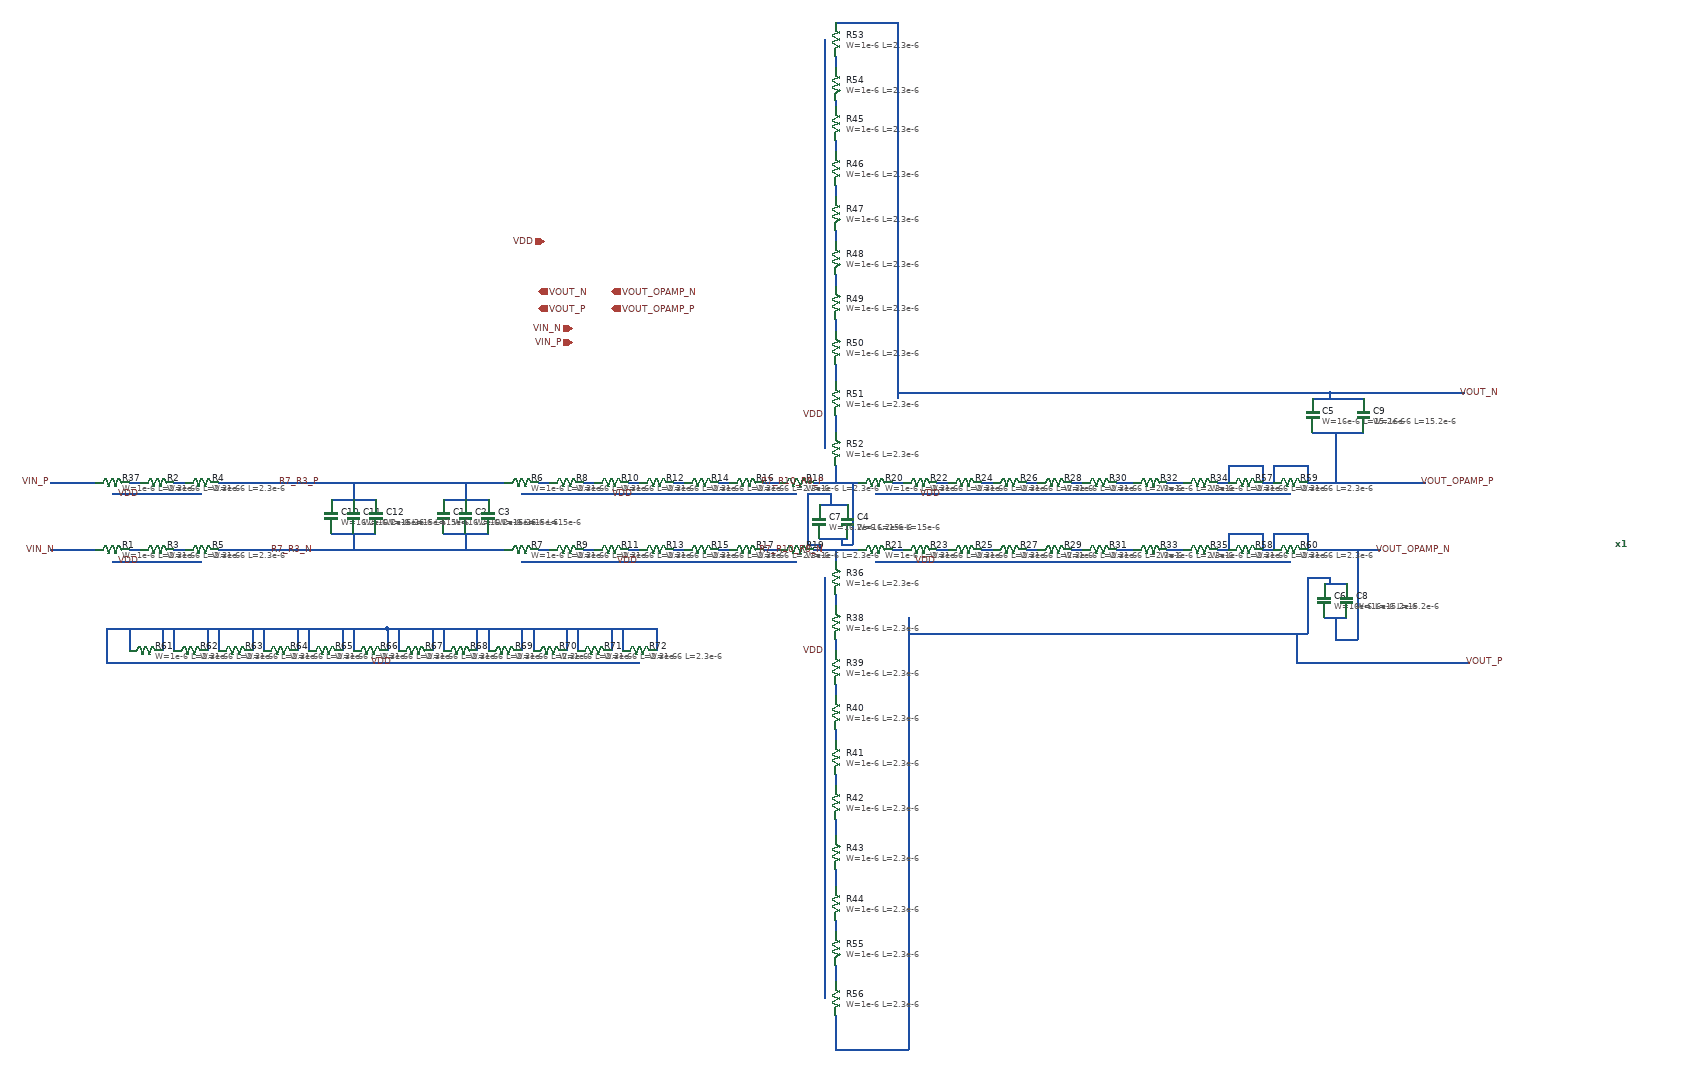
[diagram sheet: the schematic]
v {xschem version=3.4.3 file_version=1.2
}
G {}
K {}
V {}
S {}
E {}
N -170 -600 -90 -600 {
lab=VDD}
N -250 -600 -170 -600 {
lab=VDD}
N -170 -480 -90 -480 {
lab=VDD}
N -250 -480 -170 -480 {
lab=VDD}
N -220 -500 -200 -500 {
lab=#net1}
N -140 -500 -120 -500 {
lab=#net2}
N 560 -600 640 -600 {
lab=VDD}
N 480 -600 560 -600 {
lab=VDD}
N 560 -480 640 -480 {
lab=VDD}
N 480 -480 560 -480 {
lab=VDD}
N 510 -500 530 -500 {
lab=#net3}
N 590 -500 610 -500 {
lab=#net4}
N 800 -600 880 -600 {
lab=VDD}
N 720 -600 800 -600 {
lab=VDD}
N 800 -480 880 -480 {
lab=VDD}
N 720 -480 800 -480 {
lab=VDD}
N 750 -500 770 -500 {
lab=#net5}
N 830 -500 850 -500 {
lab=#net6}
N 640 -600 720 -600 {
lab=VDD}
N 640 -480 720 -480 {
lab=VDD}
N -220 -620 -200 -620 {
lab=#net7}
N -140 -620 -120 -620 {
lab=#net8}
N 510 -620 530 -620 {
lab=#net9}
N 590 -620 610 -620 {
lab=#net10}
N 750 -620 770 -620 {
lab=#net11}
N 670 -620 690 -620 {
lab=#net12}
N 830 -620 850 -620 {
lab=#net13}
N 880 -600 970 -600 {
lab=VDD}
N 910 -620 940 -620 {
lab=#net14}
N 910 -500 940 -500 {
lab=#net15}
N 880 -480 970 -480 {
lab=VDD}
N 1190 -600 1270 -600 {
lab=VDD}
N 1110 -600 1190 -600 {
lab=VDD}
N 1190 -480 1270 -480 {
lab=VDD}
N 1110 -480 1190 -480 {
lab=VDD}
N 1140 -500 1160 -500 {
lab=#net16}
N 1220 -500 1240 -500 {
lab=#net17}
N 1430 -600 1510 -600 {
lab=VDD}
N 1350 -600 1430 -600 {
lab=VDD}
N 1430 -480 1510 -480 {
lab=VDD}
N 1350 -480 1430 -480 {
lab=VDD}
N 1380 -500 1400 -500 {
lab=#net18}
N 1460 -500 1480 -500 {
lab=#net19}
N 1270 -600 1350 -600 {
lab=VDD}
N 1270 -480 1350 -480 {
lab=VDD}
N 1140 -620 1160 -620 {
lab=#net20}
N 1220 -620 1240 -620 {
lab=#net21}
N 1380 -620 1400 -620 {
lab=#net22}
N 1300 -620 1320 -620 {
lab=#net23}
N 1460 -620 1480 -620 {
lab=#net24}
N 1510 -600 1600 -600 {
lab=VDD}
N 1540 -620 1570 -620 {
lab=#net25}
N 1540 -500 1570 -500 {
lab=#net26}
N 1510 -480 1600 -480 {
lab=VDD}
N 1600 -480 1690 -480 {
lab=VDD}
N 1600 -600 1690 -600 {
lab=VDD}
N 1630 -620 1660 -620 {
lab=#net27}
N 1630 -500 1660 -500 {
lab=#net28}
N 1020 -370 1020 -290 {
lab=VDD}
N 1020 -450 1020 -370 {
lab=VDD}
N 1040 -420 1040 -400 {
lab=#net29}
N 1040 -340 1040 -320 {
lab=#net30}
N 1020 -130 1020 -50 {
lab=VDD}
N 1020 -210 1020 -130 {
lab=VDD}
N 1040 -180 1040 -160 {
lab=#net31}
N 1040 -100 1040 -80 {
lab=#net32}
N 1020 -290 1020 -210 {
lab=VDD}
N 1040 -20 1040 10 {
lab=#net33}
N 1020 -50 1020 40 {
lab=VDD}
N 1020 40 1020 130 {
lab=VDD}
N 1040 70 1040 100 {
lab=#net34}
N 1020 -1180 1020 -1100 {
lab=VDD}
N 1020 -1260 1020 -1180 {
lab=VDD}
N 1020 -940 1020 -860 {
lab=VDD}
N 1020 -1020 1020 -940 {
lab=VDD}
N 1020 -1100 1020 -1020 {
lab=VDD}
N 1040 -1230 1040 -1210 {
lab=#net35}
N 1040 -1150 1040 -1130 {
lab=#net36}
N 1040 -990 1040 -970 {
lab=#net37}
N 1040 -1070 1040 -1050 {
lab=#net38}
N 1040 -910 1040 -890 {
lab=#net39}
N 1020 -860 1020 -770 {
lab=VDD}
N 1040 -830 1040 -800 {
lab=#net40}
N 1020 -770 1020 -680 {
lab=VDD}
N 1040 -740 1040 -710 {
lab=#net41}
N 1020 -1330 1020 -1260 {
lab=VDD}
N 1020 -1410 1020 -1330 {
lab=VDD}
N 1040 -1300 1040 -1290 {
lab=#net42}
N 1040 -1380 1040 -1360 {
lab=#net43}
N 1020 210 1020 300 {
lab=VDD}
N 1040 240 1040 270 {
lab=#net44}
N 1040 170 1040 180 {
lab=#net45}
N 1040 160 1040 170 {
lab=#net45}
N 1020 130 1020 210 {
lab=VDD}
N 1000 -500 1080 -500 {
lab=R7_R10_R8_N}
N 1040 -500 1040 -480 {
lab=R7_R10_R8_N}
N 1000 -620 1080 -620 {
lab=R7_R10_R8_P}
N 1040 -650 1040 -620 {
lab=R7_R10_R8_P}
N 390 -500 450 -500 {
lab=R7_R3_N}
N 390 -620 450 -620 {
lab=R7_R3_P}
N 1720 -620 1740 -620 {
lab=VOUT_OPAMP_P}
N 1720 -500 1740 -500 {
lab=VOUT_OPAMP_N}
N 1740 -530 1740 -500 {
lab=VOUT_OPAMP_N}
N 1740 -530 1800 -530 {
lab=VOUT_OPAMP_N}
N 1800 -530 1800 -500 {
lab=VOUT_OPAMP_N}
N 1800 -500 1820 -500 {
lab=VOUT_OPAMP_N}
N 1820 -530 1820 -500 {
lab=VOUT_OPAMP_N}
N 1820 -530 1880 -530 {
lab=VOUT_OPAMP_N}
N 1880 -530 1880 -500 {
lab=VOUT_OPAMP_N}
N 1880 -500 1910 -500 {
lab=VOUT_OPAMP_N}
N 1740 -650 1740 -620 {
lab=VOUT_OPAMP_P}
N 1740 -650 1800 -650 {
lab=VOUT_OPAMP_P}
N 1800 -650 1800 -620 {
lab=VOUT_OPAMP_P}
N 1800 -620 1820 -620 {
lab=VOUT_OPAMP_P}
N 1820 -650 1820 -620 {
lab=VOUT_OPAMP_P}
N 1820 -650 1880 -650 {
lab=VOUT_OPAMP_P}
N 1880 -650 1880 -620 {
lab=VOUT_OPAMP_P}
N 1880 -620 1900 -620 {
lab=VOUT_OPAMP_P}
N 1690 -600 1850 -600 {
lab=VDD}
N 1690 -480 1850 -480 {
lab=VDD}
N 330 -620 390 -620 {
lab=R7_R3_P}
N 330 -500 390 -500 {
lab=R7_R3_N}
N 340 -530 420 -530 {
lab=R7_R3_N}
N 340 -590 420 -590 {
lab=R7_R3_P}
N 380 -590 420 -590 {
lab=R7_R3_P}
N 380 -620 380 -590 {
lab=R7_R3_P}
N 380 -530 380 -500 {
lab=R7_R3_N}
N 1170 -380 1170 330 {
lab=VOUT_P}
N 1170 330 1170 390 {
lab=VOUT_P}
N 1040 390 1170 390 {
lab=VOUT_P}
N 1040 330 1040 390 {
lab=VOUT_P}
N 1040 -1440 1150 -1440 {
lab=VOUT_N}
N 1150 -1440 1150 -770 {
lab=VOUT_N}
N -260 -300 210 -300 {
lab=VDD}
N -260 -360 240 -360 {
lab=VDD}
N 240 -360 240 -320 {
lab=VDD}
N 180 -360 180 -320 {
lab=VDD}
N 100 -360 180 -360 {
lab=VDD}
N 100 -360 100 -320 {
lab=VDD}
N 80 -360 80 -320 {
lab=VDD}
N 20 -360 80 -360 {
lab=VDD}
N 20 -360 20 -320 {
lab=VDD}
N 0 -360 0 -320 {
lab=VDD}
N -60 -360 -60 -320 {
lab=VDD}
N -80 -360 -80 -320 {
lab=VDD}
N -140 -360 -80 -360 {
lab=VDD}
N -140 -360 -140 -320 {
lab=VDD}
N -160 -360 -160 -320 {
lab=VDD}
N -220 -360 -220 -320 {
lab=VDD}
N 160 -360 160 -320 {
lab=VDD}
N -360 -620 -280 -620 {
lab=VIN_P}
N -360 -500 -280 -500 {
lab=VIN_N}
N 1910 -500 2010 -500 {
lab=VOUT_OPAMP_N}
N 1900 -620 2010 -620 {
lab=VOUT_OPAMP_P}
N 1040 -260 1040 -230 {
lab=#net46}
N 1300 -500 1320 -500 {
lab=#net47}
N 720 -360 720 -320 {
lab=VDD}
N 660 -360 660 -320 {
lab=VDD}
N 580 -360 660 -360 {
lab=VDD}
N 580 -360 580 -320 {
lab=VDD}
N 560 -360 560 -320 {
lab=VDD}
N 500 -360 560 -360 {
lab=VDD}
N 500 -360 500 -320 {
lab=VDD}
N 480 -360 480 -320 {
lab=VDD}
N 420 -360 420 -320 {
lab=VDD}
N 400 -360 400 -320 {
lab=VDD}
N 340 -360 400 -360 {
lab=VDD}
N 340 -360 340 -320 {
lab=VDD}
N 320 -360 320 -320 {
lab=VDD}
N 260 -360 260 -320 {
lab=VDD}
N 640 -360 640 -320 {
lab=VDD}
N 210 -300 690 -300 {
lab=VDD}
N 240 -360 720 -360 {
lab=VDD}
N -260 -360 -260 -300 {
lab=VDD}
N 670 -500 690 -500 {
lab=#net48}
N 1010 -520 1040 -520 {
lab=R7_R10_R8_P}
N 1010 -580 1040 -580 {
lab=R7_R10_R8_N}
N 1910 -440 1950 -440 {
lab=VOUT_P}
N 1910 -380 1950 -380 {
lab=VOUT_OPAMP_N}
N 1890 -770 1980 -770 {
lab=VOUT_N}
N -60 -620 330 -620 {
lab=R7_R3_P}
N -60 -500 330 -500 {
lab=R7_R3_N}
N 140 -530 220 -530 {
lab=R7_R3_N}
N 140 -590 220 -590 {
lab=R7_R3_P}
N 180 -590 220 -590 {
lab=R7_R3_P}
N 180 -530 180 -500 {
lab=R7_R3_N}
N 180 -620 180 -590 {
lab=R7_R3_P}
N 1040 -580 1060 -580 {
lab=R7_R10_R8_N}
N 1040 -520 1060 -520 {
lab=R7_R10_R8_P}
N 1930 -660 1930 -620 {
lab=VOUT_OPAMP_P}
N 1150 -780 1830 -780 {
lab=VOUT_N}
N 1890 -710 1980 -710 {
lab=VOUT_OPAMP_P}
N 1930 -710 1930 -660 {
lab=VOUT_OPAMP_P}
N 1830 -780 1920 -780 {
lab=VOUT_N}
N 1920 -780 1920 -770 {
lab=VOUT_N}
N 1970 -500 1970 -340 {
lab=VOUT_OPAMP_N}
N 1930 -340 1970 -340 {
lab=VOUT_OPAMP_N}
N 1930 -380 1930 -340 {
lab=VOUT_OPAMP_N}
N 1920 -450 1920 -440 {
lab=VOUT_P}
N 1880 -450 1920 -450 {
lab=VOUT_P}
N 1880 -450 1880 -350 {
lab=VOUT_P}
N 1170 -350 1880 -350 {
lab=VOUT_P}
N 1070 -620 1070 -510 {
lab=R7_R10_R8_P}
N 1050 -510 1070 -510 {
lab=R7_R10_R8_P}
N 1050 -520 1050 -510 {
lab=R7_R10_R8_P}
N 1010 -510 1010 -500 {
lab=R7_R10_R8_N}
N 990 -510 1010 -510 {
lab=R7_R10_R8_N}
N 990 -600 990 -510 {
lab=R7_R10_R8_N}
N 990 -600 1030 -600 {
lab=R7_R10_R8_N}
N 1030 -600 1030 -580 {
lab=R7_R10_R8_N}
N 2010 -620 2090 -620 {
lab=VOUT_OPAMP_P}
N 1860 -350 1860 -300 {
lab=VOUT_P}
N 1920 -780 2160 -780 {
lab=VOUT_N}
N 1860 -300 2170 -300 {
lab=VOUT_P}
C {devices/iopin.sym} 520 -1050 0 0 {name=p21 lab=VDD}
C {devices/opin.sym} 510 -960 0 0 {name=p36 lab=VOUT_N}
C {devices/opin.sym} 510 -930 0 0 {name=p37 lab=VOUT_P}
C {devices/ipin.sym} 570 -895 0 0 {name=p14 lab=VIN_N
}
C {devices/ipin.sym} 570 -870 0 0 {name=p72 lab=VIN_P}
C {symbols/ppolyf_u.sym} -250 -620 3 0 {name=R37
W=1e-6
L=2.3e-6
model=ppolyf_u
spiceprefix=X
m=1}
C {symbols/ppolyf_u.sym} -250 -500 3 0 {name=R1
W=1e-6
L=2.3e-6
model=ppolyf_u
spiceprefix=X
m=1}
C {symbols/ppolyf_u.sym} -170 -620 3 0 {name=R2
W=1e-6
L=2.3e-6
model=ppolyf_u
spiceprefix=X
m=1}
C {symbols/ppolyf_u.sym} -170 -500 3 0 {name=R3
W=1e-6
L=2.3e-6
model=ppolyf_u
spiceprefix=X
m=1}
C {symbols/ppolyf_u.sym} -90 -620 3 0 {name=R4
W=1e-6
L=2.3e-6
model=ppolyf_u
spiceprefix=X
m=1}
C {symbols/ppolyf_u.sym} -90 -500 3 0 {name=R5
W=1e-6
L=2.3e-6
model=ppolyf_u
spiceprefix=X
m=1}
C {symbols/ppolyf_u.sym} 480 -620 3 0 {name=R6
W=1e-6
L=2.3e-6
model=ppolyf_u
spiceprefix=X
m=1}
C {symbols/ppolyf_u.sym} 480 -500 3 0 {name=R7
W=1e-6
L=2.3e-6
model=ppolyf_u
spiceprefix=X
m=1}
C {symbols/ppolyf_u.sym} 560 -620 3 0 {name=R8
W=1e-6
L=2.3e-6
model=ppolyf_u
spiceprefix=X
m=1}
C {symbols/ppolyf_u.sym} 560 -500 3 0 {name=R9
W=1e-6
L=2.3e-6
model=ppolyf_u
spiceprefix=X
m=1}
C {symbols/ppolyf_u.sym} 640 -620 3 0 {name=R10
W=1e-6
L=2.3e-6
model=ppolyf_u
spiceprefix=X
m=1}
C {symbols/ppolyf_u.sym} 640 -500 3 0 {name=R11
W=1e-6
L=2.3e-6
model=ppolyf_u
spiceprefix=X
m=1}
C {symbols/ppolyf_u.sym} 720 -620 3 0 {name=R12
W=1e-6
L=2.3e-6
model=ppolyf_u
spiceprefix=X
m=1}
C {symbols/ppolyf_u.sym} 720 -500 3 0 {name=R13
W=1e-6
L=2.3e-6
model=ppolyf_u
spiceprefix=X
m=1}
C {symbols/ppolyf_u.sym} 800 -620 3 0 {name=R14
W=1e-6
L=2.3e-6
model=ppolyf_u
spiceprefix=X
m=1}
C {symbols/ppolyf_u.sym} 800 -500 3 0 {name=R15
W=1e-6
L=2.3e-6
model=ppolyf_u
spiceprefix=X
m=1}
C {symbols/ppolyf_u.sym} 880 -620 3 0 {name=R16
W=1e-6
L=2.3e-6
model=ppolyf_u
spiceprefix=X
m=1}
C {symbols/ppolyf_u.sym} 880 -500 3 0 {name=R17
W=1e-6
L=2.3e-6
model=ppolyf_u
spiceprefix=X
m=1}
C {symbols/ppolyf_u.sym} 970 -620 3 0 {name=R18
W=1e-6
L=2.3e-6
model=ppolyf_u
spiceprefix=X
m=1}
C {symbols/ppolyf_u.sym} 970 -500 3 0 {name=R19
W=1e-6
L=2.3e-6
model=ppolyf_u
spiceprefix=X
m=1}
C {symbols/ppolyf_u.sym} 1110 -620 3 0 {name=R20
W=1e-6
L=2.3e-6
model=ppolyf_u
spiceprefix=X
m=1}
C {symbols/ppolyf_u.sym} 1110 -500 3 0 {name=R21
W=1e-6
L=2.3e-6
model=ppolyf_u
spiceprefix=X
m=1}
C {symbols/ppolyf_u.sym} 1190 -620 3 0 {name=R22
W=1e-6
L=2.3e-6
model=ppolyf_u
spiceprefix=X
m=1}
C {symbols/ppolyf_u.sym} 1190 -500 3 0 {name=R23
W=1e-6
L=2.3e-6
model=ppolyf_u
spiceprefix=X
m=1}
C {symbols/ppolyf_u.sym} 1270 -620 3 0 {name=R24
W=1e-6
L=2.3e-6
model=ppolyf_u
spiceprefix=X
m=1}
C {symbols/ppolyf_u.sym} 1270 -500 3 0 {name=R25
W=1e-6
L=2.3e-6
model=ppolyf_u
spiceprefix=X
m=1}
C {symbols/ppolyf_u.sym} 1350 -620 3 0 {name=R26
W=1e-6
L=2.3e-6
model=ppolyf_u
spiceprefix=X
m=1}
C {symbols/ppolyf_u.sym} 1350 -500 3 0 {name=R27
W=1e-6
L=2.3e-6
model=ppolyf_u
spiceprefix=X
m=1}
C {symbols/ppolyf_u.sym} 1430 -620 3 0 {name=R28
W=1e-6
L=2.3e-6
model=ppolyf_u
spiceprefix=X
m=1}
C {symbols/ppolyf_u.sym} 1430 -500 3 0 {name=R29
W=1e-6
L=2.3e-6
model=ppolyf_u
spiceprefix=X
m=1}
C {symbols/ppolyf_u.sym} 1510 -620 3 0 {name=R30
W=1e-6
L=2.3e-6
model=ppolyf_u
spiceprefix=X
m=1}
C {symbols/ppolyf_u.sym} 1510 -500 3 0 {name=R31
W=1e-6
L=2.3e-6
model=ppolyf_u
spiceprefix=X
m=1}
C {symbols/ppolyf_u.sym} 1600 -620 3 0 {name=R32
W=1e-6
L=2.3e-6
model=ppolyf_u
spiceprefix=X
m=1}
C {symbols/ppolyf_u.sym} 1600 -500 3 0 {name=R33
W=1e-6
L=2.3e-6
model=ppolyf_u
spiceprefix=X
m=1}
C {symbols/ppolyf_u.sym} 1690 -620 3 0 {name=R34
W=1e-6
L=2.3e-6
model=ppolyf_u
spiceprefix=X
m=1}
C {symbols/ppolyf_u.sym} 1690 -500 3 0 {name=R35
W=1e-6
L=2.3e-6
model=ppolyf_u
spiceprefix=X
m=1}
C {symbols/ppolyf_u.sym} 1040 -450 0 0 {name=R36
W=1e-6
L=2.3e-6
model=ppolyf_u
spiceprefix=X
m=1}
C {symbols/ppolyf_u.sym} 1040 -370 0 0 {name=R38
W=1e-6
L=2.3e-6
model=ppolyf_u
spiceprefix=X
m=1}
C {symbols/ppolyf_u.sym} 1040 -290 0 0 {name=R39
W=1e-6
L=2.3e-6
model=ppolyf_u
spiceprefix=X
m=1}
C {symbols/ppolyf_u.sym} 1040 -210 0 0 {name=R40
W=1e-6
L=2.3e-6
model=ppolyf_u
spiceprefix=X
m=1}
C {symbols/ppolyf_u.sym} 1040 -130 0 0 {name=R41
W=1e-6
L=2.3e-6
model=ppolyf_u
spiceprefix=X
m=1}
C {symbols/ppolyf_u.sym} 1040 -50 0 0 {name=R42
W=1e-6
L=2.3e-6
model=ppolyf_u
spiceprefix=X
m=1}
C {symbols/ppolyf_u.sym} 1040 40 0 0 {name=R43
W=1e-6
L=2.3e-6
model=ppolyf_u
spiceprefix=X
m=1}
C {symbols/ppolyf_u.sym} 1040 130 0 0 {name=R44
W=1e-6
L=2.3e-6
model=ppolyf_u
spiceprefix=X
m=1}
C {symbols/ppolyf_u.sym} 1040 -1260 0 0 {name=R45
W=1e-6
L=2.3e-6
model=ppolyf_u
spiceprefix=X
m=1}
C {symbols/ppolyf_u.sym} 1040 -1180 0 0 {name=R46
W=1e-6
L=2.3e-6
model=ppolyf_u
spiceprefix=X
m=1}
C {symbols/ppolyf_u.sym} 1040 -1100 0 0 {name=R47
W=1e-6
L=2.3e-6
model=ppolyf_u
spiceprefix=X
m=1}
C {symbols/ppolyf_u.sym} 1040 -1020 0 0 {name=R48
W=1e-6
L=2.3e-6
model=ppolyf_u
spiceprefix=X
m=1}
C {symbols/ppolyf_u.sym} 1040 -940 0 0 {name=R49
W=1e-6
L=2.3e-6
model=ppolyf_u
spiceprefix=X
m=1}
C {symbols/ppolyf_u.sym} 1040 -860 0 0 {name=R50
W=1e-6
L=2.3e-6
model=ppolyf_u
spiceprefix=X
m=1}
C {symbols/ppolyf_u.sym} 1040 -770 0 0 {name=R51
W=1e-6
L=2.3e-6
model=ppolyf_u
spiceprefix=X
m=1}
C {symbols/ppolyf_u.sym} 1040 -680 0 0 {name=R52
W=1e-6
L=2.3e-6
model=ppolyf_u
spiceprefix=X
m=1}
C {symbols/ppolyf_u.sym} 1040 -1410 0 0 {name=R53
W=1e-6
L=2.3e-6
model=ppolyf_u
spiceprefix=X
m=1}
C {symbols/ppolyf_u.sym} 1040 -1330 0 0 {name=R54
W=1e-6
L=2.3e-6
model=ppolyf_u
spiceprefix=X
m=1}
C {symbols/ppolyf_u.sym} 1040 210 0 0 {name=R55
W=1e-6
L=2.3e-6
model=ppolyf_u
spiceprefix=X
m=1}
C {symbols/ppolyf_u.sym} 1040 300 0 0 {name=R56
W=1e-6
L=2.3e-6
model=ppolyf_u
spiceprefix=X
m=1}
C {symbols/ppolyf_u.sym} 1770 -620 3 0 {name=R57
W=1e-6
L=2.3e-6
model=ppolyf_u
spiceprefix=X
m=1}
C {symbols/ppolyf_u.sym} 1770 -500 3 0 {name=R58
W=1e-6
L=2.3e-6
model=ppolyf_u
spiceprefix=X
m=1}
C {symbols/ppolyf_u.sym} 1850 -620 3 0 {name=R59
W=1e-6
L=2.3e-6
model=ppolyf_u
spiceprefix=X
m=1}
C {symbols/ppolyf_u.sym} 1850 -500 3 0 {name=R60
W=1e-6
L=2.3e-6
model=ppolyf_u
spiceprefix=X
m=1}
C {symbols/cap_mim_2p0fF.sym} 340 -560 0 0 {name=C1
W=16.2e-6
L=15e-6
model=cap_mim_2f0_m4m5_noshield
spiceprefix=X
m=1}
C {symbols/cap_mim_2p0fF.sym} 380 -560 0 0 {name=C2
W=16.2e-6
L=15e-6
model=cap_mim_2f0_m4m5_noshield
spiceprefix=X
m=1}
C {symbols/cap_mim_2p0fF.sym} 420 -560 0 0 {name=C3
W=16.2e-6
L=15e-6
model=cap_mim_2f0_m4m5_noshield
spiceprefix=X
m=1}
C {symbols/cap_mim_2p0fF.sym} 1060 -550 0 0 {name=C4
W=16.2e-6
L=15e-6
model=cap_mim_2f0_m4m5_noshield
spiceprefix=X
m=1}
C {symbols/cap_mim_2p0fF.sym} 1890 -740 0 0 {name=C5
W=16e-6
L=15.2e-6
model=cap_mim_2f0_m4m5_noshield
spiceprefix=X
m=1}
C {symbols/cap_mim_2p0fF.sym} 1910 -410 0 0 {name=C6
W=16e-6
L=15.2e-6
model=cap_mim_2f0_m4m5_noshield
spiceprefix=X
m=1}
C {symbols/ppolyf_u.sym} -190 -320 3 0 {name=R61
W=1e-6
L=2.3e-6
model=ppolyf_u
spiceprefix=X
m=1}
C {symbols/ppolyf_u.sym} -110 -320 3 0 {name=R62
W=1e-6
L=2.3e-6
model=ppolyf_u
spiceprefix=X
m=1}
C {symbols/ppolyf_u.sym} -30 -320 3 0 {name=R63
W=1e-6
L=2.3e-6
model=ppolyf_u
spiceprefix=X
m=1}
C {symbols/ppolyf_u.sym} 50 -320 3 0 {name=R64
W=1e-6
L=2.3e-6
model=ppolyf_u
spiceprefix=X
m=1}
C {symbols/ppolyf_u.sym} 130 -320 3 0 {name=R65
W=1e-6
L=2.3e-6
model=ppolyf_u
spiceprefix=X
m=1}
C {symbols/ppolyf_u.sym} 210 -320 3 0 {name=R66
W=1e-6
L=2.3e-6
model=ppolyf_u
spiceprefix=X
m=1}
C {devices/lab_pin.sym} -200 -480 3 0 {name=p3 sig_type=std_logic lab=VDD}
C {devices/lab_pin.sym} -200 -600 3 0 {name=p7 sig_type=std_logic lab=VDD}
C {devices/lab_pin.sym} 690 -480 3 0 {name=p2 sig_type=std_logic lab=VDD}
C {devices/lab_pin.sym} 680 -600 3 0 {name=p10 sig_type=std_logic lab=VDD}
C {devices/lab_pin.sym} 1220 -480 3 0 {name=p11 sig_type=std_logic lab=VDD}
C {devices/lab_pin.sym} 1230 -600 3 0 {name=p12 sig_type=std_logic lab=VDD}
C {devices/lab_pin.sym} 1020 -320 0 0 {name=p13 sig_type=std_logic lab=VDD}
C {devices/lab_pin.sym} 1020 -740 0 0 {name=p15 sig_type=std_logic lab=VDD}
C {devices/lab_pin.sym} -360 -620 0 0 {name=p16 sig_type=std_logic lab=VIN_P}
C {symbols/ppolyf_u.sym} 290 -320 3 0 {name=R67
W=1e-6
L=2.3e-6
model=ppolyf_u
spiceprefix=X
m=1}
C {symbols/ppolyf_u.sym} 370 -320 3 0 {name=R68
W=1e-6
L=2.3e-6
model=ppolyf_u
spiceprefix=X
m=1}
C {symbols/ppolyf_u.sym} 450 -320 3 0 {name=R69
W=1e-6
L=2.3e-6
model=ppolyf_u
spiceprefix=X
m=1}
C {symbols/ppolyf_u.sym} 530 -320 3 0 {name=R70
W=1e-6
L=2.3e-6
model=ppolyf_u
spiceprefix=X
m=1}
C {symbols/ppolyf_u.sym} 610 -320 3 0 {name=R71
W=1e-6
L=2.3e-6
model=ppolyf_u
spiceprefix=X
m=1}
C {symbols/ppolyf_u.sym} 690 -320 3 0 {name=R72
W=1e-6
L=2.3e-6
model=ppolyf_u
spiceprefix=X
m=1}
C {devices/lab_pin.sym} 250 -300 3 0 {name=p20 sig_type=std_logic lab=VDD}
C {symbols/cap_mim_2p0fF.sym} 1010 -550 0 0 {name=C7
W=16.2e-6
L=15e-6
model=cap_mim_2f0_m4m5_noshield
spiceprefix=X
m=1}
C {symbols/cap_mim_2p0fF.sym} 1950 -410 0 0 {name=C8
W=16e-6
L=15.2e-6
model=cap_mim_2f0_m4m5_noshield
spiceprefix=X
m=1}
C {symbols/cap_mim_2p0fF.sym} 1980 -740 0 0 {name=C9
W=16e-6
L=15.2e-6
model=cap_mim_2f0_m4m5_noshield
spiceprefix=X
m=1}
C {symbols/cap_mim_2p0fF.sym} 140 -560 0 0 {name=C10
W=16.2e-6
L=15e-6
model=cap_mim_2f0_m4m5_noshield
spiceprefix=X
m=1}
C {symbols/cap_mim_2p0fF.sym} 180 -560 0 0 {name=C11
W=16.2e-6
L=15e-6
model=cap_mim_2f0_m4m5_noshield
spiceprefix=X
m=1}
C {symbols/cap_mim_2p0fF.sym} 220 -560 0 0 {name=C12
W=16.2e-6
L=15e-6
model=cap_mim_2f0_m4m5_noshield
spiceprefix=X
m=1}
C {devices/lab_pin.sym} 120 -620 1 0 {name=p23 sig_type=std_logic lab=R7_R3_P}
C {devices/lab_pin.sym} 110 -500 1 0 {name=p24 sig_type=std_logic lab=R7_R3_N}
C {devices/lab_pin.sym} 1020 -620 1 0 {name=p26 sig_type=std_logic lab=R7_R10_R8_P}
C {devices/lab_pin.sym} 1020 -500 3 0 {name=p27 sig_type=std_logic lab=R7_R10_R8_N}
C {devices/lab_pin.sym} -350 -500 0 0 {name=p17 sig_type=std_logic lab=VIN_N}
C {devices/opin.sym} 640 -960 0 0 {name=p1 lab=VOUT_OPAMP_N}
C {devices/opin.sym} 640 -930 0 0 {name=p4 lab=VOUT_OPAMP_P}
C {devices/lab_pin.sym} 2150 -780 2 0 {name=p5 sig_type=std_logic lab=VOUT_N}
C {devices/lab_pin.sym} 2080 -620 2 0 {name=p6 sig_type=std_logic lab=VOUT_OPAMP_P}
C {devices/lab_pin.sym} 2000 -500 2 0 {name=p8 sig_type=std_logic lab=VOUT_OPAMP_N}
C {devices/lab_pin.sym} 2160 -300 2 0 {name=p9 sig_type=std_logic lab=VOUT_P}
C {Folded_Cascode_Diff.sym} 2430 -510 0 0 {name=x1}
